# Bundled ASAP7 routing technology (tools/chip_assembly/v41_die.py): every routing layer's
# pitch, width, spacing and offset multiplied by k = 16; one routing track = 16 ASAP7 tracks.
VERSION 5.8 ;
BUSBITCHARS "[]" ;
DIVIDERCHAR "/" ;
UNITS
  DATABASE MICRONS 1000 ;
END UNITS
MANUFACTURINGGRID 0.001 ;
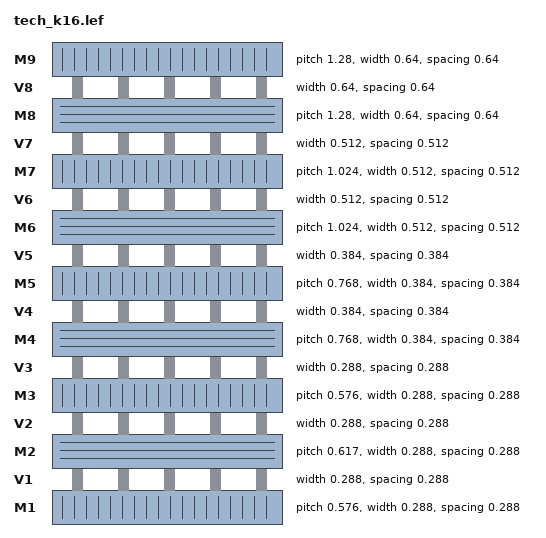
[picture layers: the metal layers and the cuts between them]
LAYER M1
  TYPE ROUTING ;
  DIRECTION VERTICAL ;
  PITCH 0.576 ;
  WIDTH 0.288 ;
  SPACING 0.288 ;
  OFFSET 0.144 ;
END M1
LAYER V1
  TYPE CUT ;
  SPACING 0.288 ;
  WIDTH 0.288 ;
END V1
LAYER M2
  TYPE ROUTING ;
  DIRECTION HORIZONTAL ;
  PITCH 0.617 ;
  WIDTH 0.288 ;
  SPACING 0.288 ;
  OFFSET 0.144 ;
END M2
LAYER V2
  TYPE CUT ;
  SPACING 0.288 ;
  WIDTH 0.288 ;
END V2
LAYER M3
  TYPE ROUTING ;
  DIRECTION VERTICAL ;
  PITCH 0.576 ;
  WIDTH 0.288 ;
  SPACING 0.288 ;
  OFFSET 0.144 ;
END M3
LAYER V3
  TYPE CUT ;
  SPACING 0.288 ;
  WIDTH 0.288 ;
END V3
LAYER M4
  TYPE ROUTING ;
  DIRECTION HORIZONTAL ;
  PITCH 0.768 ;
  WIDTH 0.384 ;
  SPACING 0.384 ;
  OFFSET 0.192 ;
END M4
LAYER V4
  TYPE CUT ;
  SPACING 0.384 ;
  WIDTH 0.384 ;
END V4
LAYER M5
  TYPE ROUTING ;
  DIRECTION VERTICAL ;
  PITCH 0.768 ;
  WIDTH 0.384 ;
  SPACING 0.384 ;
  OFFSET 0.192 ;
END M5
LAYER V5
  TYPE CUT ;
  SPACING 0.384 ;
  WIDTH 0.384 ;
END V5
LAYER M6
  TYPE ROUTING ;
  DIRECTION HORIZONTAL ;
  PITCH 1.024 ;
  WIDTH 0.512 ;
  SPACING 0.512 ;
  OFFSET 0.256 ;
END M6
LAYER V6
  TYPE CUT ;
  SPACING 0.512 ;
  WIDTH 0.512 ;
END V6
LAYER M7
  TYPE ROUTING ;
  DIRECTION VERTICAL ;
  PITCH 1.024 ;
  WIDTH 0.512 ;
  SPACING 0.512 ;
  OFFSET 0.256 ;
END M7
LAYER V7
  TYPE CUT ;
  SPACING 0.512 ;
  WIDTH 0.512 ;
END V7
LAYER M8
  TYPE ROUTING ;
  DIRECTION HORIZONTAL ;
  PITCH 1.280 ;
  WIDTH 0.640 ;
  SPACING 0.640 ;
  OFFSET 1.856 ;
END M8
LAYER V8
  TYPE CUT ;
  SPACING 0.640 ;
  WIDTH 0.640 ;
END V8
LAYER M9
  TYPE ROUTING ;
  DIRECTION VERTICAL ;
  PITCH 1.280 ;
  WIDTH 0.640 ;
  SPACING 0.640 ;
  OFFSET 1.856 ;
END M9
VIA VIA12 DEFAULT
  LAYER M1 ;
    RECT -0.144 -0.144 0.144 0.144 ;
  LAYER V1 ;
    RECT -0.144 -0.144 0.144 0.144 ;
  LAYER M2 ;
    RECT -0.144 -0.144 0.144 0.144 ;
END VIA12
VIA VIA23 DEFAULT
  LAYER M2 ;
    RECT -0.144 -0.144 0.144 0.144 ;
  LAYER V2 ;
    RECT -0.144 -0.144 0.144 0.144 ;
  LAYER M3 ;
    RECT -0.144 -0.144 0.144 0.144 ;
END VIA23
VIA VIA34 DEFAULT
  LAYER M3 ;
    RECT -0.144 -0.144 0.144 0.144 ;
  LAYER V3 ;
    RECT -0.144 -0.144 0.144 0.144 ;
  LAYER M4 ;
    RECT -0.192 -0.192 0.192 0.192 ;
END VIA34
VIA VIA45 DEFAULT
  LAYER M4 ;
    RECT -0.192 -0.192 0.192 0.192 ;
  LAYER V4 ;
    RECT -0.192 -0.192 0.192 0.192 ;
  LAYER M5 ;
    RECT -0.192 -0.192 0.192 0.192 ;
END VIA45
VIA VIA56 DEFAULT
  LAYER M5 ;
    RECT -0.192 -0.192 0.192 0.192 ;
  LAYER V5 ;
    RECT -0.192 -0.192 0.192 0.192 ;
  LAYER M6 ;
    RECT -0.256 -0.256 0.256 0.256 ;
END VIA56
VIA VIA67 DEFAULT
  LAYER M6 ;
    RECT -0.256 -0.256 0.256 0.256 ;
  LAYER V6 ;
    RECT -0.256 -0.256 0.256 0.256 ;
  LAYER M7 ;
    RECT -0.256 -0.256 0.256 0.256 ;
END VIA67
VIA VIA78 DEFAULT
  LAYER M7 ;
    RECT -0.256 -0.256 0.256 0.256 ;
  LAYER V7 ;
    RECT -0.256 -0.256 0.256 0.256 ;
  LAYER M8 ;
    RECT -0.320 -0.320 0.320 0.320 ;
END VIA78
VIA VIA89 DEFAULT
  LAYER M8 ;
    RECT -0.320 -0.320 0.320 0.320 ;
  LAYER V8 ;
    RECT -0.320 -0.320 0.320 0.320 ;
  LAYER M9 ;
    RECT -0.320 -0.320 0.320 0.320 ;
END VIA89
SITE bsite
  CLASS CORE ;
  SYMMETRY Y ;
  SIZE 0.864 BY 4.320 ;
END bsite
END LIBRARY
